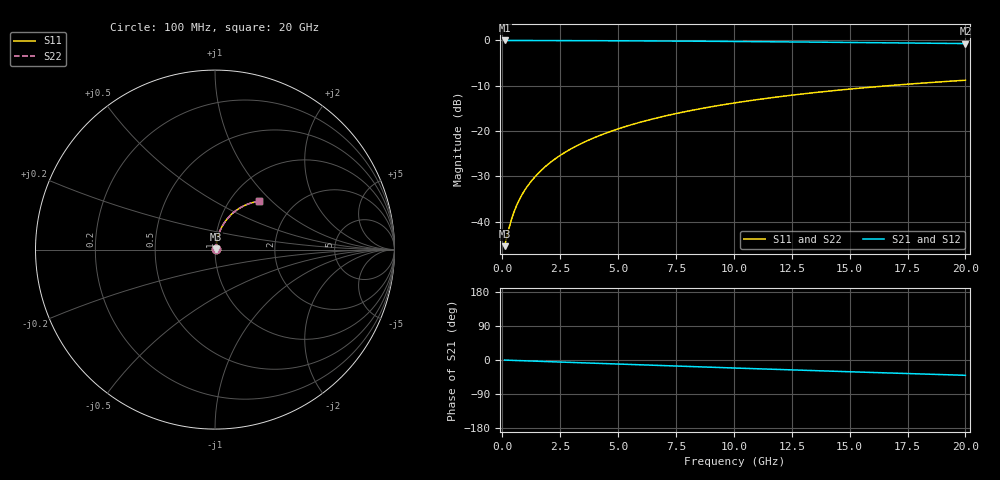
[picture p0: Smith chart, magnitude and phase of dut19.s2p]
! Touchstone file exported from HFSS 2026.1.0
!  File:  C:/ffzhzh/LocalFiles/Ansys_Project_Files/temp_test_BSMRDL_19_1782907499_13352.aedt
!  Generated:  08:06:12 PM Jul  1, 2026
!  Design:  BSMRDL
!  Project:  temp_test_BSMRDL_19_1782907499_13352
! Variables:
!  h_bsmrdl = 2.29um
!  h_ox = 20um
!  h_rdl = 5um
!  h_sub = 80um
!  h_tmrdl = 5um
!  h_tsv = 80um
!  h_via = 3um
!  l_bsmrdl = 590.57um
!  l_sub = 990.57um
!  l_tmrdl = 200um
!  m_sub = 200um
!  pitch = 40.94um
!  r_tsv = 6um
!  s_tmrdl = 10um
!  w_bsmrdl = 19.94um
!  w_sub = 500um
!  w_tmrdl = 12um
!  x_tsv_center1 = 206um
!  x_tsv_center2 = 816.51um
!  x_tsv_center3 = 1028.51um
!  x_tsv_center4 = 1639.02um
!  x_tsv_center5 = 1851.02um
!  x_tsv_center6 = 2461.53um
# GHz S MA R 50.000000
! Terminal data exported
! Port[1] = BSM_RDL1_1_T1
! Port[2] = BSM_RDL1_1_T2
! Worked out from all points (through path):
!   200 points, 100 MHz to 20 GHz, reference 50 ohm
!   highest |S21| = -0.04 dB at 100 MHz (marker M1); lowest = -0.7 dB at 20 GHz (marker M2)
!   group delay of S21, straight-line fit = 5.62 ps
!   lowest |S11| = -45.4 dB at 100 MHz (marker M3), VSWR 1.01, Z = 50.5 + j0.24 ohm
!   |S11| at or under -10 dB: start of sweep to 16.69 GHz
!   |S22| runs from -45.4 to -8.8 dB; largest |S21 - S12| = 3.4e-15
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0.1  0.005398 26.1  0.9952 -0.2  0.9952 -0.2  0.005398 26.1
! Gamma 0 0 0 0
! Port Impedance 50 0 50 0
0.3  0.008712 53.5  0.9949 -0.7  0.9949 -0.7  0.008712 53.5
0.4  0.0107 59.6  0.9947 -0.9  0.9947 -0.9  0.0107 59.6
0.5  0.01273 63.6  0.9945 -1.1  0.9945 -1.1  0.01273 63.6
0.6  0.01477 66.4  0.9943 -1.3  0.9943 -1.3  0.01477 66.4
0.7  0.01681 68.5  0.9941 -1.6  0.9941 -1.6  0.01681 68.5
0.9  0.02089 71.4  0.9938 -2.0  0.9938 -2.0  0.02089 71.4
1.2  0.02702 74.1  0.9935 -2.6  0.9935 -2.6  0.02702 74.1
1.4  0.03113 75.3  0.9933 -3.1  0.9933 -3.1  0.03113 75.3
1.7  0.03732 76.4  0.9929 -3.7  0.9929 -3.7  0.03732 76.4
2.2  0.0477 77.3  0.9923 -4.8  0.9923 -4.8  0.0477 77.3
2.8  0.06019 77.6  0.9915 -6.0  0.9915 -6.0  0.06019 77.6
3.5  0.07475 77.2  0.9904 -7.5  0.9904 -7.5  0.07475 77.2
4.2  0.08925 76.5  0.989 -9.0  0.989 -9.0  0.08925 76.5
5  0.1057 75.3  0.9872 -10.7  0.9872 -10.7  0.1057 75.3
5.9  0.124 73.9  0.9848 -12.6  0.9848 -12.6  0.124 73.9
6.8  0.142 72.3  0.9821 -14.5  0.9821 -14.5  0.142 72.3
8.3  0.1714 69.6  0.9769 -17.6  0.9769 -17.6  0.1714 69.6
10.1  0.2054 66.2  0.9697 -21.3  0.9697 -21.3  0.2054 66.2
13.4  0.2637 59.9  0.9544 -27.9  0.9544 -27.9  0.2637 59.9
16.7  0.3164 53.7  0.9374 -34.3  0.9374 -34.3  0.3164 53.7
20  0.363 47.7  0.9198 -40.4  0.9198 -40.4  0.363 47.7
